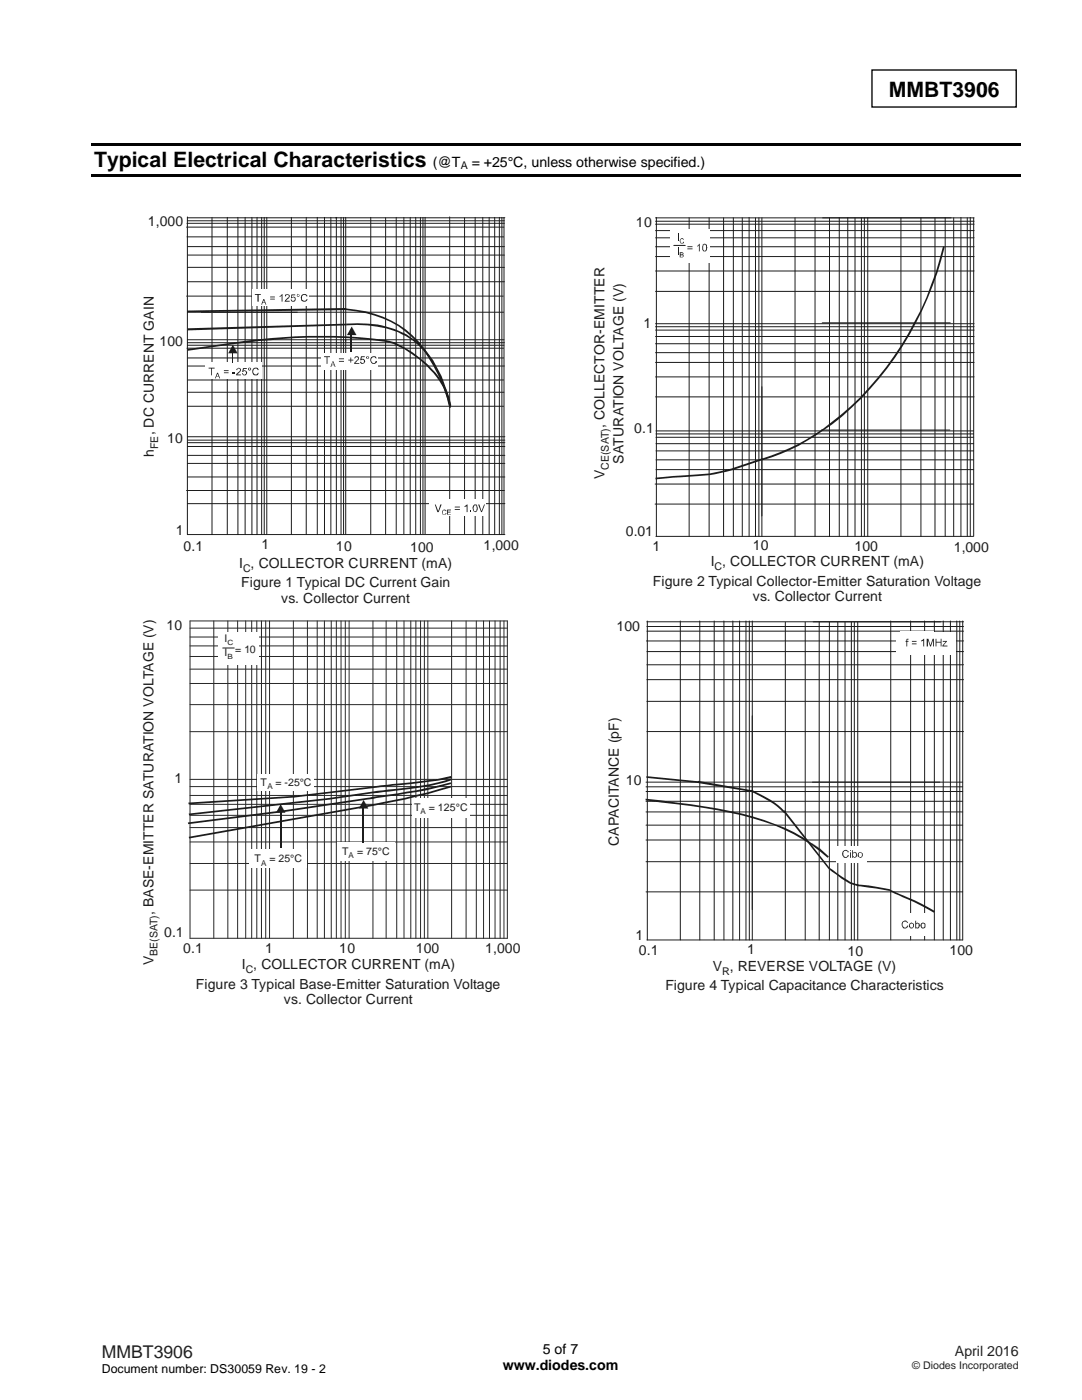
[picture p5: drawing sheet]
<svg xmlns="http://www.w3.org/2000/svg" width="216mm" height="279mm" viewBox="0 0 216 279" stroke-linecap="round" stroke-linejoin="round" font-family="sans-serif">
<defs><g id="words">
<g font-size="4.2">
<text x="177.4" y="19.3">MMBT3906</text>
<text x="18.8" y="33.4">Typical Electrical Characteristics</text>
</g>
<text font-size="3.5" fill="#231f20" x="20.3" y="270.9">MMBT3906</text>
<g font-size="2.8">
<text x="86.4" y="33.4">(@T</text>
<text x="94.1" y="33.4">= +25°C, unless otherwise specified.)</text>
<text x="100.3" y="273.5">www.diodes.com</text>
<text x="108.3" y="270.2">5 of 7</text>
</g>
<g font-size="2.8" fill="#1f1a17">
<text x="29.5" y="45.2">1,000</text>
<text x="126.9" y="45.3">10</text>
<text x="128.4" y="65.4">1</text>
<text x="31.8" y="69">100</text>
<text x="30.7" y="86.9" transform="rotate(-90 30.7 86.9)">, DC CURRENT GAIN</text>
<text x="33.3" y="88.3">10</text>
<text x="120.6" y="85.5" transform="rotate(-90 120.6 85.5)">, COLLECTOR-EMITTER</text>
<text x="126.6" y="86.4">0.1</text>
<text x="30.7" y="91.2" transform="rotate(-90 30.7 91.2)">h</text>
<text x="120.6" y="95.7" transform="rotate(-90 120.6 95.7)">V</text>
<text x="124.4" y="92.5" transform="rotate(-90 124.4 92.5)">SATURATION VOLTAGE (V)</text>
<text x="35.1" y="106.7">1</text>
<text x="124.9" y="106.9">0.01</text>
<text x="36.6" y="110.1">0.1</text>
<text x="47.7" y="113.3">I , COLLECTOR CURRENT (mA)</text>
<text x="52.2" y="109.6">1</text>
<text x="67" y="110">10</text>
<text x="81.9" y="110.1">100</text>
<text x="96.5" y="109.7">1,000</text>
<text x="130.2" y="109.9">1</text>
<text x="141.8" y="113">I , COLLECTOR CURRENT (mA)</text>
<text x="150.2" y="109.7">10</text>
<text x="170.5" y="110">100</text>
<text x="190.3" y="110.1">1,000</text>
<text x="48.1" y="117.2">Figure 1 Typical DC Current Gain</text>
<text x="130.3" y="116.9">Figure 2 Typical Collector-Emitter Saturation Voltage</text>
<text x="33.2" y="125.8">10</text>
<text x="56.1" y="120.3">vs. Collector Current</text>
<text x="123" y="125.9">100</text>
<text x="150.2" y="120">vs. Collector Current</text>
<text x="34.9" y="156.3">1</text>
<text x="124.8" y="156.7">10</text>
<text x="123.5" y="168.9" transform="rotate(-90 123.5 168.9)">CAPACITANCE (pF)</text>
<text x="30.6" y="182.6" transform="rotate(-90 30.6 182.6)">, BASE-EMITTER SATURATION VOLTAGE (V)</text>
<text x="32.7" y="187.1">0.1</text>
<text x="36.5" y="190.1">0.1</text>
<text x="52.9" y="190.2">1</text>
<text x="67.7" y="190.1">10</text>
<text x="83" y="190.2">100</text>
<text x="96.8" y="190.1">1,000</text>
<text x="126.8" y="187.5">1</text>
<text x="127.5" y="190.6">0.1</text>
<text x="149.1" y="190.4">1</text>
<text x="169.1" y="190.7">10</text>
<text x="189.5" y="190.6">100</text>
<text x="30.6" y="192.6" transform="rotate(-90 30.6 192.6)">V</text>
<text x="39.1" y="197.3">Figure 3 Typical Base-Emitter Saturation Voltage</text>
<text x="48.3" y="193.4">I , COLLECTOR CURRENT (mA)</text>
<text x="132.8" y="197.5">Figure 4 Typical Capacitance Characteristics</text>
<text x="142.2" y="193.7">V , REVERSE VOLTAGE (V)</text>
<text x="56.7" y="200.4">vs. Collector Current</text>
</g>
<text font-size="2.8" fill="#231f20" x="190.5" y="270.6">April 2016</text>
<text font-size="2.5" x="20.3" y="274">Document number: DS30059 Rev. 19 - 2</text>
<text font-size="2.1" x="91.9" y="33.7">A</text>
<g font-size="2.1" fill="#1f1a17">
<text x="31.5" y="89.6" transform="rotate(-90 31.5 89.6)">FE</text>
<text x="121.5" y="93.8" transform="rotate(-90 121.5 93.8)">CE(SAT)</text>
<text x="142.6" y="113.8">C</text>
<text x="48.5" y="114.1">C</text>
<text x="44.8" y="128.2">I</text>
<text x="44.8" y="131">I</text>
<text x="46.9" y="130.4">= 10</text>
<text x="52" y="156.8">T</text>
<text x="55" y="156.8">= -25°C</text>
<text x="82.6" y="161.9">T</text>
<text x="85.6" y="161.9">= 125°C</text>
<text x="50.8" y="172.1">T</text>
<text x="53.8" y="172.1">= 25°C</text>
<text x="68.3" y="170.6">T</text>
<text x="71.3" y="170.6">= 75°C</text>
<text x="31.5" y="190.8" transform="rotate(-90 31.5 190.8)">BE(SAT)</text>
<text x="49" y="194.2">C</text>
<text x="144.1" y="194.5">R</text>
</g>
<text font-size="2.1" fill="#231f20" x="182" y="273.2">© Diodes Incorporated</text>
<g font-size="1.6" fill="#1f1a17">
<text x="53.4" y="157.4">A</text>
<text x="83.9" y="162.5">A</text>
<text x="52.1" y="172.7">A</text>
<text x="69.6" y="171.3">A</text>
</g>
<g font-size="1.4" fill="#1f1a17">
<text x="45.4" y="128.8">C</text>
<text x="45.4" y="131.6">B</text>
</g>
</g></defs>
<path d="M174 14h28.8v7.4h-28.8z" fill="none" stroke="#000" stroke-width=".26"/>
<g fill="#000">
<path d="M18.3 28.6h185.4v.5h-185.4z" fill-rule="evenodd"/>
<path d="M18.3 34.7h185.4v.5h-185.4z" fill-rule="evenodd"/>
</g>
<g fill="#fff">
<path d="M84.8 99.5h12v4.3h-12z" fill-rule="evenodd"/>
<path d="M85.7 99.2h11.7v4.4h-11.7z" fill-rule="evenodd"/>
</g>
<g fill="none" stroke="#1f1a17" stroke-width=".2">
<path d="M37.2 45.3h63.4M37.2 59.1h63.2M37.3 44.6h63.3M37.3 47.3h63.2M37.4 43.3v63.4h63.3M37.4 53.4h63.2M37.4 56.2h63.2M42.3 43.4v63.3M45.4 43.4v63.3M47.5 43.4v63.3M48.9 43.4v63.3M50.3 43.4v63.3"/>
<path d="M51.3 43.4v63.3M52.2 43.4v63.3M52.7 43.4v63.3M53.2 43.4v63.3M58.1 43.4v63.3M67 43.5h33.7M68 43.4v63.3M68.6 43.4v63.3M81.9 43.4v63.2M83 43.4v63.2M83.9 43.4v63.2M84.4 43.4v63.2"/>
<path d="M84.8 43.4v63.2M97.6 43.4v63.3M98.7 43.4v63.3M99.6 43.4v63.3M100.1 43.4v63.3M100.6 43.4v63.3M37.3 69.5h63.2M37.4 78.3h63.2M37.4 62.3h63.1M37.4 71.4h63.1M66.4 73h34.2M67.5 68.4h33.1"/>
<path d="M69 67.8v38.9M37.2 97.9h63.4M37.4 87.2h63.3M37.4 95.2h63.3M37.4 89.1h63.3M37.4 88.3h63.3M37.4 87.8h63.3M37.4 90.9h63.3M37.4 81.1h63.1M37.4 100.5h63.3"/>
</g>
<path d="M37.4 65.5l31.7-.9v.3l-31.7 1z" fill="#1f1a17"/>
<g fill="none" stroke="#1f1a17" stroke-width=".2">
<path d="M37.4 49.2h63.2M37.4 50.9h63.2M37.4 44.1h63.2M37.4 43.5h29.8M61.1 43.4v63.3M63.3 43.4v63.3M64.7 43.4v63.3M66 43.4v63.3M67.1 43.4v63.3M69 43.4v24.7M74 43.4v63.3M76.9 43.5v63.1"/>
<path d="M79.1 43.4v63.2M80.6 43.4v63.2M89.7 43.3v63.4M92.7 43.5v63.2M94.8 43.4v63.3M96.3 43.4v63.3M37.4 73h29M37.4 75.8h63.1M37.4 68.9h63.2M37.4 68.4h30.1M37.4 67.8h63.2M37.4 92.5h63.3"/>
</g>
<g fill="#1f1a17">
<path d="M37.4 62l31.7-.5v.4l-31.7 .4z"/>
<path d="M69.1 64.6a20.8 20.8 0 0 1 12 2.1l2 1.4-.2 .3a15.8 15.8 0 0 0-9.6-3.5h-4.2zM82.9 68.4l.2-.3a18.7 18.7 0 0 1 5.7 8.8l1.1 4.1-.3 .1a24.4 24.4 0 0 0-4.9-11z"/>
<path d="M69 61.5a21.3 21.3 0 0 1 13.4 5.5l-.3 .2a20.9 20.9 0 0 0-13.1-5.3zM82.1 67.2l.3-.2a25.8 25.8 0 0 1 6.1 9.5l1.6 4.4-.4 .1a34.3 34.3 0 0 0-6.4-12.6z"/>
<path d="M77 67.9l-.1 .3zM77 67.9v.2zM77 67.9l1.7 .4-.2 .4-1.6-.5zM78.7 68.3l2.1 1.1-.1 .3-2.2-1zM80.8 69.4a21.6 21.6 0 0 1 8.3 8.2 9 9 0 0 1 .9 3.7l-.4 .1a11.6 11.6 0 0 0-3.8-7.6 21.3 21.3 0 0 0-5.1-4.1z"/>
</g>
<g fill="#fff">
<path d="M40.9 72.4h11.4v3.3h-11.4z" fill-rule="evenodd"/>
<path d="M64.2 70.4h11.2v3.3h-11.2z" fill-rule="evenodd"/>
<path d="M50.4 57.7h11.3v3.3h-11.3z" fill-rule="evenodd"/>
<path d="M85.7 99.7h11.3v3.3h-11.3z" fill-rule="evenodd"/>
</g>
<g fill="#1f1a17">
<path d="M41.6 73.4h1.2v.2h-.5v1.3h-.2v-1.3h-.5z" fill-rule="evenodd"/>
<path d="M44.7 73.9h.9v.2h-.9zM44.7 74.3h.9v.2h-.9z" fill-rule="evenodd"/>
<path d="M46.4 74.2h.6v.3h-.6z" fill-rule="evenodd"/>
<path d="M47.2 73.6a.48 .48 0 0 1 .8-.1 .48 .48 0 0 1-.2 .8l-.4 .4h.7v.2h-1v-.2a1.25 1.25 0 0 0 .8-1l-.4-.1-.2 .3-.2-.1z" fill-rule="evenodd"/>
<path d="M48.5 73.5h.8v.1h-.6l-.1 .4a.49 .49 0 0 1 .6 .2 .49 .49 0 0 1-.3 .7 .49 .49 0 0 1-.6-.4h.2v.2a.33 .33 0 0 0 .5 0 .33 .33 0 0 0 0-.5 .33 .33 0 0 0-.5 0h-.2z" fill-rule="evenodd"/>
<path d="M49.5 73.7a.3 .3 0 0 1 .6 0 .3 .3 0 0 1-.6 0zM49.6 73.6a.2 .2 0 0 0 .4 0 .2 .2 0 0 0-.4 0z" fill-rule="evenodd"/>
<path d="M50.5 73.6l.4-.2a.56 .56 0 0 1 .7 .4l-.2 .1a.53 .53 0 0 0-.8-.2 .53 .53 0 0 0 .1 .9l.2 .1h.3l.2-.3h.2a.69 .69 0 0 1-.9 .5 .69 .69 0 0 1-.3-1z" fill-rule="evenodd"/>
<path d="M43.3 74.4h.2l.4 1.1h-.2v-.3h-.5l-.1 .3h-.2zM43.4 74.6l-.2 .5h.4z" fill-rule="evenodd"/>
<path d="M64.7 71.1h1.1v.2h-.5v1.3h-.1v-1.3h-.5z" fill-rule="evenodd"/>
<path d="M67.6 71.5h1v.2h-1zM67.6 72h1v.2h-1z" fill-rule="evenodd"/>
<path d="M69.5 71.8h.4v-.4h.2v.4h.4v.1h-.4v.5h-.2v-.5h-.4z" fill-rule="evenodd"/>
<path d="M70.8 71.2a.5 .5 0 0 1 .8 .2 .5 .5 0 0 1-.4 .7l-.3 .4h.8v.1h-1l.1-.3 .5-.4 .1-.4a.3 .3 0 0 0-.3-.2 .3 .3 0 0 0-.3 .2h-.1z" fill-rule="evenodd"/>
<path d="M72 71.1h.8v.2h-.6l-.1 .4a.51 .51 0 0 1 .8 .5 .51 .51 0 0 1-.9 .3l-.1-.1v-.2h.1a.33 .33 0 0 0 .5 .2 .33 .33 0 0 0 .1-.5l-.1-.1-.5 .1h-.1z" fill-rule="evenodd"/>
<path d="M73 71.3a.3 .3 0 0 1 .6 0 .3 .3 0 0 1-.6 0zM73.2 71.3l.1 .2 .3-.1-.2-.2z" fill-rule="evenodd"/>
<path d="M74.1 71.3l.5-.2a.46 .46 0 0 1 .6 .4h-.2a.55 .55 0 0 0-.7-.1 .55 .55 0 0 0-.2 .8 .55 .55 0 0 0 .7 .2l.2-.4 .2 .1a.73 .73 0 0 1-1 .4 .73 .73 0 0 1-.2-1.1z" fill-rule="evenodd"/>
<path d="M66.4 72.1h.1l.5 1.1h-.2l-.1-.3h-.5l-.1 .3h-.2zM66.4 72.3l-.2 .5h.4l-.2-.6z" fill-rule="evenodd"/>
<path d="M50.9 58.7h1.1v.1h-.4v1.4h-.2v-1.4h-.5z" fill-rule="evenodd"/>
<path d="M53.9 59.2h.9v.2h-.9zM53.9 59.6h.9v.2h-.9z" fill-rule="evenodd"/>
<path d="M55.8 59.1l.6-.4v1.5h-.2v-1.2l-.4 .3z" fill-rule="evenodd"/>
<path d="M57 58.8a.52 .52 0 0 1 .6-.1 .52 .52 0 0 1 .2 .6l-.8 .7h.8v.2h-1l.8-1a.3 .3 0 0 0-.3-.4 .3 .3 0 0 0-.3 .4l-.1-.1z" fill-rule="evenodd"/>
<path d="M58.1 58.8h.8v.1h-.6l-.1 .4a.52 .52 0 0 1 .8 .2 .52 .52 0 0 1-.4 .7 .52 .52 0 0 1-.6-.4h.2a.33 .33 0 0 0 .5 .2 .33 .33 0 0 0 .1-.5 .33 .33 0 0 0-.5-.1l-.2 .1z" fill-rule="evenodd"/>
<path d="M59.2 59a.3 .3 0 0 1 .6 0 .3 .3 0 0 1-.6 0zM59.3 58.9a.2 .2 0 0 0 .4 0 .2 .2 0 0 0-.4 0z" fill-rule="evenodd"/>
<path d="M60.3 58.8l.6-.1 .5 .4-.3 .1a.48 .48 0 0 0-.7-.3 .48 .48 0 0 0-.1 .7 .47 .47 0 0 0 .4 .4 .47 .47 0 0 0 .5-.3h.2a.69 .69 0 0 1-1 .5 .69 .69 0 0 1-.3-1z" fill-rule="evenodd"/>
<path d="M52.6 59.7h.1l.4 1.1h-.1l-.1-.3h-.5l-.1 .3h-.2zM52.6 59.8l-.1 .6h.3z" fill-rule="evenodd"/>
<path d="M86.8 100.7h.1l.5 1.3 .5-1.3h.2l-.6 1.5h-.2z" fill-rule="evenodd"/>
<path d="M90.7 101.1h1.1v.2h-1.1zM90.7 101.6h1.1v.2h-1.1z" fill-rule="evenodd"/>
<path d="M92.7 101l.6-.3v1.5h-.2v-1.2l-.3 .2z" fill-rule="evenodd"/>
<path d="M93.9 102h.2v.2h-.2z" fill-rule="evenodd"/>
<path d="M94.5 100.8a.43 .43 0 0 1 .4-.1 .43 .43 0 0 1 .3 .4 .6 .6 0 0 1 .1 .8 .6 .6 0 0 1-.8 .1l-.2-.6zM94.6 100.9l-.1 .5 .1 .6h.3h.2v-.6v-.5z" fill-rule="evenodd"/>
<path d="M95.4 100.7h.3l.4 1.3 .5-1.3h.2l-.6 1.5h-.2z" fill-rule="evenodd"/>
<path d="M88.3 101.9l.5-.2 .3 .2v.1a.4 .4 0 0 0-.7 .1 .4 .4 0 0 0 .4 .5l.3-.2a.44 .44 0 0 1-.6 .3 .44 .44 0 0 1-.3-.6z" fill-rule="evenodd"/>
<path d="M89.2 101.7h.8v.2h-.6v.2h.5v.2h-.5v.3l.6 .1h-.8z" fill-rule="evenodd"/>
<path d="M70.2 65.2l.9 1.7h-1.9l1-1.7 .9 1.7z" fill-rule="evenodd"/>
</g>
<path d="M70.1 66.7v3.5" fill="none" stroke="#1f1a17" stroke-width=".26"/>
<path d="M46.5 68.8l.9 1.7h-1.9l1-1.7 .9 1.7z" fill-rule="evenodd" fill="#1f1a17"/>
<g fill="#1f1a17">
<path d="M46.4 70.4h.1v2h-.1z"/>
<path d="M37.4 69.7a265.2 265.2 0 0 1 19-2.4l.1 .3a247.6 247.6 0 0 0-19 2.4zM56.4 67.3a97.5 97.5 0 0 1 20.6 .6v.3a96.6 96.6 0 0 0-20.5-.6z"/>
</g>
<g fill="none" stroke="#1f1a17" stroke-width=".2">
<path d="M130.8 54.1h63.6M130.8 44.2h63.6M130.8 44.7h63.6M130.8 46h63.6M130.8 47.5h63.6M130.8 49.2h63.6M130.8 51.2h63.6M130.8 58.2h63.6M131 43.4v63.6M137.5 43.5v63.5M141.5 43.5v63.5M144.4 43.5v63.5"/>
<path d="M146.3 43.5v63.5M148.1 43.5v63.5M149.5 43.4v63.6M150.7 43.5v63.5M151.4 43.5v63.5M164.2 43.5h25.6M130.8 75.2h63.6M130.8 65.2h63.6M130.8 65.9h63.6M130.8 67.2h63.6M130.8 68.6h63.6M130.8 70.4h63.6"/>
<path d="M130.8 72.3h63.6M130.8 79.2h63.6M152 77.2v25.8M164.1 64.4h25.5M130.7 96.6h63.6M130.9 86.6h63.4M130.9 87.3h63.4M130.9 88.5h63.4M130.9 90h63.4M130.9 91.8h63.4M130.9 93.7h63.4M163.9 85.8h25.6"/>
<path d="M130.7 100.6h63.6M130.9 107h63.3"/>
</g>
<path d="M146.1 93.5l6.1-2.1 .1 .4-6.1 2z" fill="#1f1a17"/>
<g fill="none" stroke="#1f1a17" stroke-width=".2">
<path d="M130.8 43.5h63.6M152 43.5v63.5M158.6 43.5v63.5M162.6 43.5v63.5M165.5 43.5v63.5M167.5 43.5v63.5M169.2 43.5v63.5M170.6 43.5v63.5M171.9 43.5v63.5M172.5 43.5v63.5M173.1 43.4v63.6M179.8 43.5v63.5"/>
<path d="M183.8 43.5v63.5M186.6 43.5v63.5M188.6 43.5v63.5M190.3 43.5v63.5M191.7 43.4v63.6M193 43.5v63.5M193.6 43.4v63.6M194.3 43.5v63.5M130.8 64.6h63.6M130.9 86h63.4"/>
</g>
<g fill="#1f1a17">
<path d="M152.1 91.5l.1 .4zM152.1 91.5l.1 .2zM152.1 91.5a47.8 47.8 0 0 0 7.1-2.9l.2 .4a42.9 42.9 0 0 1-7.2 2.9zM159.2 88.6a47.3 47.3 0 0 0 6.6-4.2l.2 .3-3.2 2.2-3.4 2.1zM188.2 49.2h.3a64.1 64.1 0 0 1-22.5 35.5l-.2-.3a62.8 62.8 0 0 0 21.7-32.7z"/>
<path d="M130.8 95.3l6.4-.5v.4l-6.4 .5zM137.2 94.8a31.2 31.2 0 0 0 9-1.3v.3l-2.4 .6a27.2 27.2 0 0 1-6.6 .8z"/>
</g>
<path d="M133.7 45.8h8v6.7h-8z" fill-rule="evenodd" fill="#fff"/>
<g fill="#1f1a17">
<path d="M135.2 46.5h.2v1.5h-.2z" fill-rule="evenodd"/>
<path d="M135.7 47.7a.36 .36 0 0 1 .4-.2 .36 .36 0 0 1 .3 .4 .35 .35 0 0 0-.5-.1 .35 .35 0 0 0-.1 .5 .35 .35 0 0 0 .5 .1l.1-.2 .1 .1a.43 .43 0 0 1-.5 .3 .43 .43 0 0 1-.4-.4z" fill-rule="evenodd"/>
<path d="M135.2 49.3h.2v1.5h-.2z" fill-rule="evenodd"/>
<path d="M135.6 50.3h.5a.29 .29 0 0 1 .2 .2 .29 .29 0 0 1-.1 .4 .27 .27 0 0 1 .2 .3 .27 .27 0 0 1-.3 .2h-.5zM135.8 50.5v.3l.4-.1v-.2zM135.8 50.9v.4h.3l.2-.2-.1-.2z" fill-rule="evenodd"/>
<path d="M137.2 49.2h1v.1h-1zM137.2 49.6h1v.1h-1z" fill-rule="evenodd"/>
<path d="M139.1 49.1l.5-.5v1.6h-.1v-1.2l-.4 .2z" fill-rule="evenodd"/>
<path d="M140.2 48.8a.5 .5 0 0 1 .6-.1 .5 .5 0 0 1 .3 .5 .59 .59 0 0 1-.1 .8 .59 .59 0 0 1-.7 .1l-.2-.3zM140.4 48.9l-.1 .8 .3 .4a.91 .91 0 0 0 0-1.3z" fill-rule="evenodd"/>
</g>
<path d="M134.4 49h2.3" fill="none" stroke="#1f1a17" stroke-width=".2"/>
<g fill="none" stroke="#23282b" stroke-width=".2">
<path d="M37.9 136.4h63.3M37.9 133.5h63.3M37.9 131h63.3M37.9 128.9h63.3M37.9 127.1h63.3M37.9 125.4h63.3M37.9 123.9h63.3v63.4h-63.3zM42.7 123.9v63.4M45.5 123.9v63.4M47.4 123.9v63.4M49 123.9v63.4M50.2 123.9v63.4"/>
<path d="M51.2 123.9v63.4M52.2 123.9v63.4M53 123.9v63.4M53.8 123.9v63.4M58.5 123.9v63.4M61.3 123.9v63.4M63.3 123.9v63.4M64.7 123.9v63.4M66.1 123.9v63.4M67.1 123.9v63.4M68 123.9v63.4M68.9 123.9v63.4"/>
<path d="M69.7 123.9v63.4M74.4 123.9v63.4M77 123.9v63.4M79.2 123.9v63.4M80.6 123.9v63.4M82 123.9v63.4M83 123.9v63.4M83.9 123.9v63.4M84.7 123.9v63.4M85.4 123.9v63.4M90.1 123.9v63.4M93 123.9v63.4"/>
<path d="M95 123.9v63.4M96.5 123.9v63.4M97.7 123.9v63.4M98.8 123.9v63.4M99.8 123.9v63.4M100.6 123.9v63.4M37.9 158.7h63.3M37.9 157h63.3M37.9 146h63.3M37.9 140.6h63.3M37.9 155.5h63.3M37.9 177.6h63.3"/>
<path d="M37.9 172.3h63.3M37.9 168h63.3M37.9 165.2h63.3M37.9 162.7h63.3M37.9 160.5h63.3"/>
</g>
<path d="M43.6 126.2h8.1v6.6h-8.1z" fill-rule="evenodd" fill="#fff"/>
<path d="M44.4 129.3h2.3" fill="none" stroke="#1f1a17" stroke-width=".2"/>
<g fill="#1f1a17">
<path d="M37.7 167l34.7-6.1 .1 .3-34.8 6.1zM72.4 160.9l8.3-1.6 .1 .3-8.3 1.6zM80.7 159.3l4.6-1.1 4.6-1.4 .1 .3-4.6 1.4-4.6 1.1z"/>
<path d="M37.5 164.1l19.3-2.4v.3l-19.2 2.5zM56.8 161.9v.1zM56.8 161.7l16.3-2.4 .1 .3-16.4 2.4zM73.1 159.3l.1 .3zM73.1 159.3l2.7-.5 .1 .4-2.7 .4zM75.8 158.8a90.2 90.2 0 0 0 14.1-2.7l.1 .4a90.7 90.7 0 0 1-14.1 2.7z"/>
<path d="M37.7 162.4l28-3.1v.3l-28 3.1zM65.7 159.4v.2zM65.7 159.3l8.6-1.3v.3l-8.6 1.3zM74.3 158v.3zM74.3 158l4.4-.5v.3l-4.4 .5zM78.7 157.5a44 44 0 0 0 11.2-2.1l.2 .3-1.3 .4a51.5 51.5 0 0 1-10.1 1.7z"/>
<path d="M37.6 160.2l21.1-1.4v.4l-21 1.3zM58.7 159v.2zM58.7 158.8l16.2-1.9v.3l-16.2 2zM74.9 156.9l4.5-.5 .1 .3-4.6 .5zM79.4 156.4a87.4 87.4 0 0 0 10.6-1.5l.1 .4-2.7 .5-7.9 .9z"/>
</g>
<g fill="#fff">
<path d="M49.8 169.5h11.5v3.7h-11.5z" fill-rule="evenodd"/>
<path d="M67.3 168.1h11.4v3.7h-11.4z" fill-rule="evenodd"/>
<path d="M51.2 154.6h11.4v3.3h-11.4z" fill-rule="evenodd"/>
<path d="M82.2 159.3h11.5v3.8h-11.5z" fill-rule="evenodd"/>
</g>
<path d="M72.5 159.7l1 1.7h-1.9l.9-1.7 1 1.7z" fill-rule="evenodd" fill="#1f1a17"/>
<path d="M72.5 161.2v7.1" fill="none" stroke="#1f1a17" stroke-width=".25"/>
<path d="M56 160.5l.9 1.7h-1.8l.9-1.7 .9 1.7z" fill-rule="evenodd" fill="#1f1a17"/>
<path d="M56 162v7.1" fill="none" stroke="#1f1a17" stroke-width=".25"/>
<g fill="none" stroke="#1f1a17" stroke-width=".2">
<path d="M129 127.9h63.3M129.1 140h63.2M129.1 125h63.2M129.1 124.1h63.2M129.1 126h63.2M129.1 130h63.2M129.1 132.7h63.2M129.1 135.6h63.2M129.2 123.9v63.7M135.8 123.9v63.7M139.6 123.9v63.7M142.5 123.9v63.7"/>
<path d="M144.5 123.9v63.7M146.2 123.9v63.7M147.6 123.9v63.7M148.8 123.9v63.7M149.5 123.9v63.7M150.1 123.9v63.7M156.7 124.2v63.4M160.7 124.2v63.4M163.5 124.2v63.4M165.5 124.2v63.4M167.2 124.2v63.4M168.6 124.2v63.4"/>
<path d="M169.9 124.2v63.4M170.5 124.2v63.4M171.2 124.1v63.5M177.7 123.9v63.7M181.7 123.9v63.7M184.5 123.9v63.7M186.4 123.9v63.7M188.2 123.9v63.7M189.6 123.9v63.7M190.9 123.9v63.7M191.5 123.9v63.7M192.1 123.9v63.7h-63"/>
<path d="M128.9 157h63.2M128.9 156.1h63.2M128.9 158h63.2M128.9 159.9h63.2M129.1 146h63.2M128.9 172h63.2M128.9 162h63.2M128.9 164.7h63.2M128.9 167.6h63.2M128.9 178h63.2"/>
</g>
<g fill="#fff">
<path d="M178.7 126.2h12v4.5h-12z" fill-rule="evenodd"/>
<path d="M179.7 126h6.7v4.5h-6.7z" fill-rule="evenodd"/>
</g>
<g fill="#1f1a17">
<path d="M180.9 127.5h.4v.2h-.3v.2h.3v.2h-.3v.9h-.1v-.9h-.2v-.2h.2z" fill-rule="evenodd"/>
<path d="M182 127.9h.9v.2h-.9zM182 128.4h.9v.2h-.9z" fill-rule="evenodd"/>
<path d="M183.8 127.8l.6-.3v1.5h-.2v-1.2l-.3 .2z" fill-rule="evenodd"/>
<path d="M184.9 127.5h.3l.5 1.3 .4-1.3h.2v1.5h-.1v-1.3l-.4 1.3h-.2l-.4-1.3v1.3h-.3z" fill-rule="evenodd"/>
<path d="M186.7 127.5h.2v.6h.8v-.6h.2v1.5h-.2v-.7h-.8v.7h-.2z" fill-rule="evenodd"/>
<path d="M188.1 127.9h.9l-.7 .9h.8v.2h-1.1v-.2l.7-.7h-.6z" fill-rule="evenodd"/>
</g>
<g fill="#1f1a17">
<path d="M156.5 161.7l9.1 11.5-.3 .2-9-11.5z"/>
<path d="M129 154.9l10.3 1v.4l-10.3-1.1z"/>
<path d="M139.3 155.8l10.7 1.9v.3l-10.8-1.7z"/>
</g>
<g fill="#fff">
<path d="M166.8 168.8h6.2v3.3h-6.2z" fill-rule="evenodd"/>
<path d="M178.7 182.3h6.9v4.4h-6.9z" fill-rule="evenodd"/>
</g>
<g fill="#1f1a17">
<path d="M168.1 170a.67 .67 0 0 1 .7-.4 .67 .67 0 0 1 .6 .5h-.3a.43 .43 0 0 0-.5-.3 .43 .43 0 0 0-.3 .5 .5 .5 0 0 0 .2 .7 .5 .5 0 0 0 .7-.4l.2 .1a.69 .69 0 0 1-1 .5 .69 .69 0 0 1-.3-1z" fill-rule="evenodd"/>
<path d="M169.6 169.7h.2v.1h-.2zM169.6 170.1h.2v1.1h-.2z" fill-rule="evenodd"/>
<path d="M170 169.7h.2v.5a.53 .53 0 0 1 .8 .4 .53 .53 0 0 1-.8 .4v.2h-.2zM170.4 170.2a.42 .42 0 0 0-.2 .5 .42 .42 0 0 0 .5 .2l.1-.5-.2-.2z" fill-rule="evenodd"/>
<path d="M171.1 170.6a.55 .55 0 0 1 1.1 0 .55 .55 0 0 1-1.1 0zM171.4 170.3v.1a.37 .37 0 0 0 0 .5 .37 .37 0 0 0 .5 0 .37 .37 0 0 0 .1-.5l-.2-.2z" fill-rule="evenodd"/>
<path d="M180.1 183.9l.2-.1a.6 .6 0 0 1 .9 .4h-.2a.56 .56 0 0 0-.9 0 .56 .56 0 0 0 .3 .8v.1a.42 .42 0 0 0 .6-.4l.2 .1a.65 .65 0 0 1-.8 .5 .65 .65 0 0 1-.5-.8z" fill-rule="evenodd"/>
<path d="M181.4 184.7a.54 .54 0 0 1 1 0 .54 .54 0 0 1-1 0zM181.6 184.4v.1a.37 .37 0 0 0 .1 .5 .37 .37 0 0 0 .5 0 .37 .37 0 0 0 0-.5l-.3-.2z" fill-rule="evenodd"/>
<path d="M182.6 183.8h.2v.5a.47 .47 0 0 1 .8 .3v.1a.59 .59 0 0 1-.7 .6l-.1-.2v.2h-.2zM182.9 184.4v.7a.39 .39 0 0 0 .4-.4 .39 .39 0 0 0-.4-.3z" fill-rule="evenodd"/>
<path d="M183.8 184.3a.53 .53 0 0 1 .7-.1 .53 .53 0 0 1 .2 .7 .53 .53 0 0 1-.8 .3 .53 .53 0 0 1-.2-.8zM184 184.4l-.1 .5 .2 .2a.43 .43 0 0 0 .4-.4 .43 .43 0 0 0-.4-.4z" fill-rule="evenodd"/>
</g>
<g fill="#1f1a17">
<path d="M128.8 159.4a141.3 141.3 0 0 1 21.5 3.6l-.1 .3-4.6-1.1-5-.9-11.8-1.6zM150.3 163a38.2 38.2 0 0 1 13.5 6.5l1.6 1.4-.3 .3a36 36 0 0 0-14.9-7.9z"/>
<path d="M149.9 157.6l.7 .4-.1 .3-.7-.3zM150.6 158a16.9 16.9 0 0 1 6 3.9l-.2 .3-.7-.7a17.2 17.2 0 0 0-5.2-3.2z"/>
<path d="M177.6 177.6l3.5 1.5-.1 .3-2.5-1.1-.9-.5zM181.1 179.1l2.8 1.3 2.6 1.4-.2 .3-5.3-2.7z"/>
<path d="M171 176.5l.6 .1v.3l-.7-.1zM171.6 176.6l6 .9v.3l-6-.9z"/>
<path d="M165.5 173.2l-.2 .2zM165.5 173.2l1.5 1.1-.2 .2-1.5-1.1zM167 174.3l1.1 .7a5.9 5.9 0 0 0 3.2 1.5l-.1 .3-.5-.1a7.6 7.6 0 0 1-3.9-2.2z"/>
</g>
<use href="#words"/>
</svg>
